VERSION 5.8 ;
BUSBITCHARS "[]" ;
DIVIDERCHAR "/" ;
UNITS
  DATABASE MICRONS 1000 ;
END UNITS
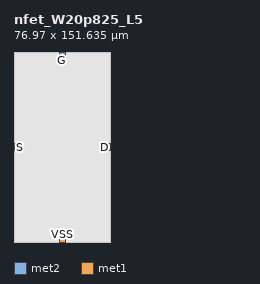
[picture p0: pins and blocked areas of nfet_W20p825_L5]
MACRO nfet_W20p825_L5
  CLASS BLOCK ;
  ORIGIN 0 0 ;
  FOREIGN nfet_W20p825_L5 0 0 ;
  SIZE 76.97 BY 151.635 ;
  SYMMETRY X Y ;
  PIN D
    DIRECTION INOUT ;
    USE SIGNAL ;
    PORT
      LAYER met2 ;
        RECT 73.89 73.315 76.97 78.315 ;
    END
  END D
  PIN G
    DIRECTION INPUT ;
    USE SIGNAL ;
    PORT
      LAYER met2 ;
        RECT 35.985 148.555 40.985 151.635 ;
    END
  END G
  PIN S
    DIRECTION INOUT ;
    USE SIGNAL ;
    PORT
      LAYER met2 ;
        RECT 0 73.315 3.08 78.315 ;
    END
  END S
  PIN VSS
    DIRECTION INOUT ;
    USE GROUND ;
    PORT
      LAYER met1 ;
        RECT 35.985 0 40.985 3.08 ;
    END
  END VSS
  OBS
    LAYER met1 ;
      RECT 0 0 76.97 151.635 ;
  END
END nfet_W20p825_L5
END LIBRARY
